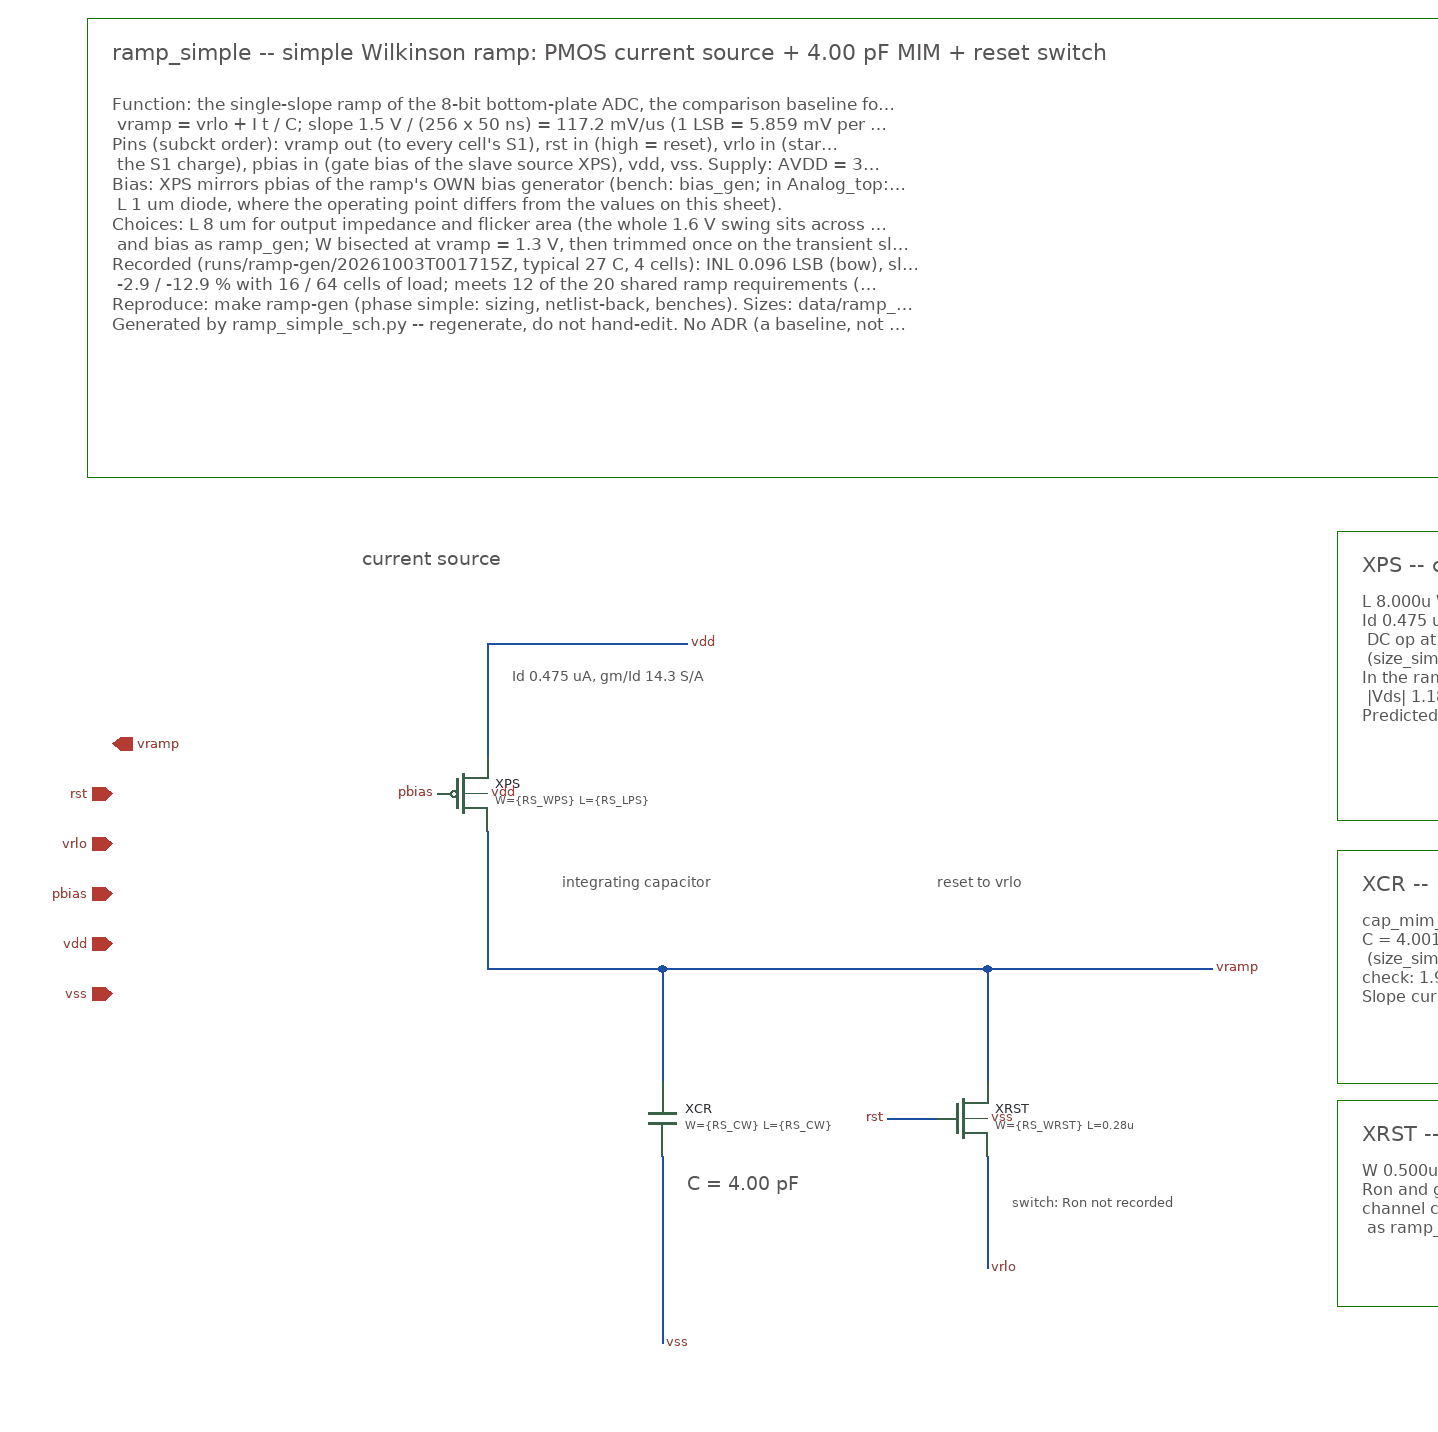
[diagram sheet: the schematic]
v {xschem version=3.4.8RC file_version=1.2}
G {}
K {}
V {}
S {}
E {}
N 320 -560 320 -470 {}
N 320 -560 480 -560 {}
N 320 -410 320 -300 {}
N 320 -300 460 -300 {}
N 460 -300 460 -210 {}
N 460 -300 720 -300 {}
N 460 -150 460 0 {}
N 640 -180 680 -180 {}
N 720 -300 720 -210 {}
N 720 -300 900 -300 {}
N 720 -150 720 -60 {}
T {ramp_simple -- simple Wilkinson ramp: PMOS current source + 4.00 pF MIM + reset switch} 20 -1045 0 0 0.70 0.70 {}
T {Function: the single-slope ramp of the 8-bit bottom-plate ADC, the comparison baseline for ramp_gen (Miller integrator).
   vramp = vrlo + I t / C; slope 1.5 V / (256 x 50 ns) = 117.2 mV/us (1 LSB = 5.859 mV per 50 ns count).
Pins (subckt order): vramp out (to every cell's S1), rst in (high = reset), vrlo in (start level 0.5 V, must sink I and
   the S1 charge), pbias in (gate bias of the slave source XPS), vdd, vss.   Supply: AVDD = 3.3 V.
Bias: XPS mirrors pbias of the ramp's OWN bias generator (bench: bias_gen; in Analog_top: bias_gen current into an
   L 1 um diode, where the operating point differs from the values on this sheet).
Choices: L 8 um for output impedance and flicker area (the whole 1.6 V swing sits across XPS); the same 4 pF MIM, slope
   and bias as ramp_gen; W bisected at vramp = 1.3 V, then trimmed once on the transient slope (size_simple.py).
Recorded (runs/ramp-gen/20261003T001715Z, typical 27 C, 4 cells): INL 0.096 LSB (bow), slope error -0.02 %,
   -2.9 / -12.9 % with 16 / 64 cells of load; meets 12 of the 20 shared ramp requirements (ramp_gen 20); COMPARISON.md.
Reproduce: make ramp-gen (phase simple: sizing, netlist-back, benches).  Sizes: data/ramp_simple_params.spice.
Generated by ramp_simple_sch.py -- regenerate, do not hand-edit.  No ADR (a baseline, not a candidate).} 20 -1003 0 0 0.40 0.40 {}
L 4 0 -1060 1745 -1060 {}
L 4 1745 -1060 1745 -693 {}
L 4 1745 -693 0 -693 {}
L 4 0 -693 0 -1060 {}
T {current source} 220 -640 0 0 0.45 0.45 {layer=13}
T {integrating capacitor} 380 -380 0 0 0.35 0.35 {layer=13}
T {reset to vrlo} 680 -380 0 0 0.35 0.35 {layer=13}
T {Id 0.475 uA, gm/Id 14.3 S/A} 340 -545 0 0 0.35 0.35 {layer=4}
T {C = 4.00 pF} 480 -140 0 0 0.45 0.45 {layer=4}
T {switch: Ron not recorded} 740 -125 0 0 0.32 0.32 {layer=4}
T {XPS -- current source (pfet_03v3)} 1020 -635 0 0 0.50 0.50 {}
T {L 8.000u  W 23.910u  nf 3  (data/ramp_simple_params.spice)
Id 0.475 uA   gm/Id 14.28 S/A   rout 730 Mohm
   DC op at vramp = 1.3 V (mid-ramp) on bias_gen, typical 27 C
   (size_simple.py -> data/sizing_simple.json = simple_size_* in runs/ramp-gen/20261003T001715Z)
In the ramp transient: mean Id 0.475 uA; at the overrange top
   |Vds| 1.18 V against Vdsat 0.09 V (margin 1.09 V, simple_nom_ps_*)
Predicted bow from gds over the 1.6 V swing: 0.15 LSB} 1020 -605 0 0 0.38 0.38 {}
L 4 1000 -650 2154 -650 {}
L 4 2154 -650 2154 -419 {}
L 4 2154 -419 1000 -419 {}
L 4 1000 -419 1000 -650 {}
T {XCR -- integrating capacitor} 1020 -380 0 0 0.50 0.50 {}
T {cap_mim_2f0_m4m5_noshield, 44.6 x 44.6 um
C = 4.001 pF: PDK model (mimcap_typical), AC at 1 kHz, 0.8 V bias
   (size_simple.py; simple_size_c in runs/ramp-gen/20261003T001715Z)
check: 1.99 fF/um2 x area + 0.238 fF/um x perimeter = 4.001 pF
Slope current I = C x SLOPE = 0.4689 uA (before the transient trim)} 1020 -350 0 0 0.38 0.38 {}
L 4 1000 -395 1835 -395 {}
L 4 1835 -395 1835 -208 {}
L 4 1835 -208 1000 -208 {}
L 4 1000 -208 1000 -395 {}
T {XRST -- reset switch (nfet_03v3)} 1020 -180 0 0 0.50 0.50 {}
T {W 0.500u  L 0.28u  nf 1; rst high shorts vramp to vrlo
Ron and gm/Id: not recorded (a switch, off during the ramp)
channel charge ~1.4 fC = ~0.2 mV pedestal on 4 pF (same switch
   as ramp_gen's XRST: ramp_gen/DESIGN_RECIPE.md s.3, derived)} 1020 -150 0 0 0.38 0.38 {}
L 4 1000 -195 1766 -195 {}
L 4 1766 -195 1766 -30 {}
L 4 1766 -30 1000 -30 {}
L 4 1000 -30 1000 -195 {}
C {devices/opin.sym} 20 -480 0 0 {name=p_vramp lab=vramp}
C {devices/ipin.sym} 20 -440 0 0 {name=p_rst lab=rst}
C {devices/ipin.sym} 20 -400 0 0 {name=p_vrlo lab=vrlo}
C {devices/ipin.sym} 20 -360 0 0 {name=p_pbias lab=pbias}
C {devices/iopin.sym} 20 -320 0 0 {name=p_vdd lab=vdd}
C {devices/iopin.sym} 20 -280 0 0 {name=p_vss lab=vss}
C {devices/lab_pin.sym} 480 -560 0 1 {name=l1 sig_type=std_logic lab=vdd}
C {symbols/pfet_03v3.sym} 300 -440 0 0 {name=XPS
L="\{RS_LPS\}"
W="\{RS_WPS\}"
nf="\{RS_NFPS\}"
m=1
model=pfet_03v3
spiceprefix=""
format="@name @pinlist @model L=@L W=@W nf=@nf m=@m"}
C {devices/lab_pin.sym} 280 -440 0 0 {name=l2 sig_type=std_logic lab=pbias}
C {devices/lab_pin.sym} 320 -440 0 1 {name=l3 sig_type=std_logic lab=vdd}
C {devices/lab_pin.sym} 900 -300 0 1 {name=l4 sig_type=std_logic lab=vramp}
C {symbols/cap_mim_2f0fF.sym} 460 -180 0 0 {name=XCR W="\{RS_CW\}" L="\{RS_CW\}" model=cap_mim_2f0_m4m5_noshield spiceprefix="" m=1}
C {devices/lab_pin.sym} 460 0 0 1 {name=l5 sig_type=std_logic lab=vss}
C {symbols/nfet_03v3.sym} 700 -180 0 0 {name=XRST
L=0.28u
W="\{RS_WRST\}"
nf=1
m=1
model=nfet_03v3
spiceprefix=""
format="@name @pinlist @model L=@L W=@W nf=@nf m=@m"}
C {devices/lab_pin.sym} 720 -180 0 1 {name=l6 sig_type=std_logic lab=vss}
C {devices/lab_pin.sym} 720 -60 0 1 {name=l7 sig_type=std_logic lab=vrlo}
C {devices/lab_pin.sym} 640 -180 0 0 {name=l8 sig_type=std_logic lab=rst}
